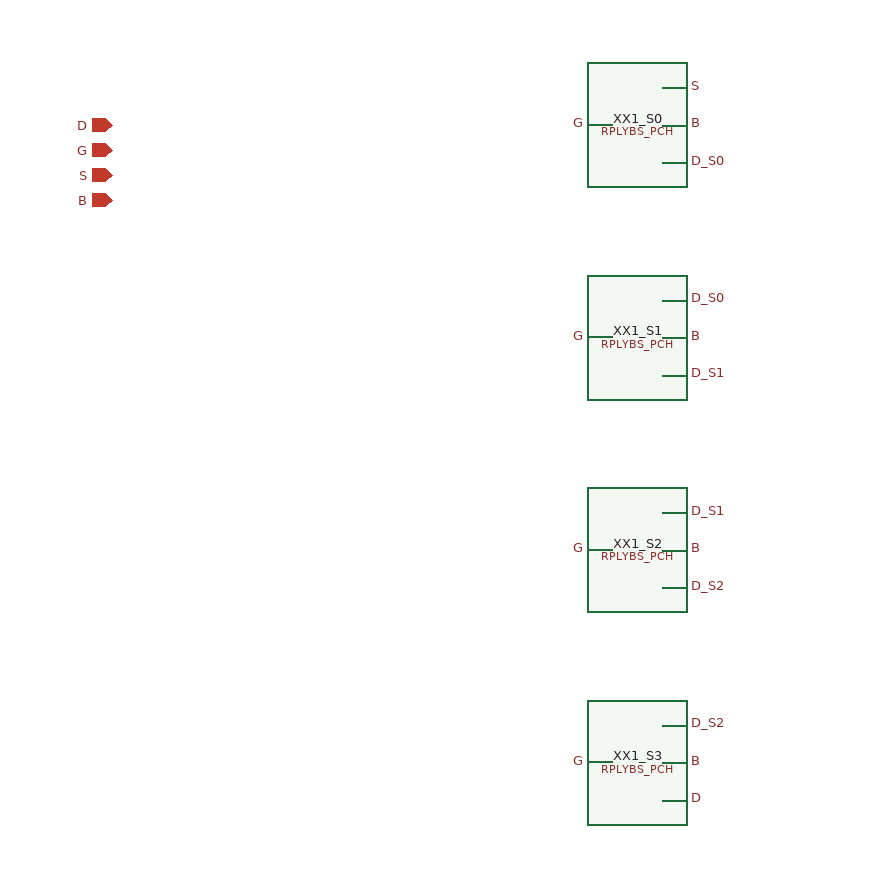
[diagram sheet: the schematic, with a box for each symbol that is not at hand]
v {xschem version=3.0.0 file_version=1.2 }
G {}
K {}
V {}
S {}
E {}
C {devices/iopin.sym} 0 0 0 0{name=p0 lab=D}
C {devices/iopin.sym} 0 20 0 0{name=p1 lab=G}
C {devices/iopin.sym} 0 40 0 0{name=p2 lab=S}
C {devices/iopin.sym} 0 60 0 0{name=p3 lab=B}
C {RPLY_BIAS_SKY130NM/RPLYBS_PCH.sym} 400 0 0 0 {name=XX1_S0}
N 460.0 30.0 440.0 30.0{lab=D_S0}
C {devices/lab_pin.sym} 460.0 30.0 2 0  {name=l0 sig_type=std_logic lab=D_S0 }
N 380.0 0.0 400.0 0.0{lab=G}
C {devices/lab_pin.sym} 380.0 0.0 0 0  {name=l1 sig_type=std_logic lab=G }
N 460.0 -30.0 440.0 -30.0{lab=S}
C {devices/lab_pin.sym} 460.0 -30.0 2 0  {name=l2 sig_type=std_logic lab=S }
N 460.0 0.0 440.0 0.0{lab=B}
C {devices/lab_pin.sym} 460.0 0.0 2 0  {name=l3 sig_type=std_logic lab=B }
C {RPLY_BIAS_SKY130NM/RPLYBS_PCH.sym} 400 170.0 0 0 {name=XX1_S1}
N 460.0 200.0 440.0 200.0{lab=D_S1}
C {devices/lab_pin.sym} 460.0 200.0 2 0  {name=l4 sig_type=std_logic lab=D_S1 }
N 380.0 170.0 400.0 170.0{lab=G}
C {devices/lab_pin.sym} 380.0 170.0 0 0  {name=l5 sig_type=std_logic lab=G }
N 460.0 140.0 440.0 140.0{lab=D_S0}
C {devices/lab_pin.sym} 460.0 140.0 2 0  {name=l6 sig_type=std_logic lab=D_S0 }
N 460.0 170.0 440.0 170.0{lab=B}
C {devices/lab_pin.sym} 460.0 170.0 2 0  {name=l7 sig_type=std_logic lab=B }
C {RPLY_BIAS_SKY130NM/RPLYBS_PCH.sym} 400 340.0 0 0 {name=XX1_S2}
N 460.0 370.0 440.0 370.0{lab=D_S2}
C {devices/lab_pin.sym} 460.0 370.0 2 0  {name=l8 sig_type=std_logic lab=D_S2 }
N 380.0 340.0 400.0 340.0{lab=G}
C {devices/lab_pin.sym} 380.0 340.0 0 0  {name=l9 sig_type=std_logic lab=G }
N 460.0 310.0 440.0 310.0{lab=D_S1}
C {devices/lab_pin.sym} 460.0 310.0 2 0  {name=l10 sig_type=std_logic lab=D_S1 }
N 460.0 340.0 440.0 340.0{lab=B}
C {devices/lab_pin.sym} 460.0 340.0 2 0  {name=l11 sig_type=std_logic lab=B }
C {RPLY_BIAS_SKY130NM/RPLYBS_PCH.sym} 400 510.0 0 0 {name=XX1_S3}
N 460.0 540.0 440.0 540.0{lab=D}
C {devices/lab_pin.sym} 460.0 540.0 2 0  {name=l12 sig_type=std_logic lab=D }
N 380.0 510.0 400.0 510.0{lab=G}
C {devices/lab_pin.sym} 380.0 510.0 0 0  {name=l13 sig_type=std_logic lab=G }
N 460.0 480.0 440.0 480.0{lab=D_S2}
C {devices/lab_pin.sym} 460.0 480.0 2 0  {name=l14 sig_type=std_logic lab=D_S2 }
N 460.0 510.0 440.0 510.0{lab=B}
C {devices/lab_pin.sym} 460.0 510.0 2 0  {name=l15 sig_type=std_logic lab=B }
